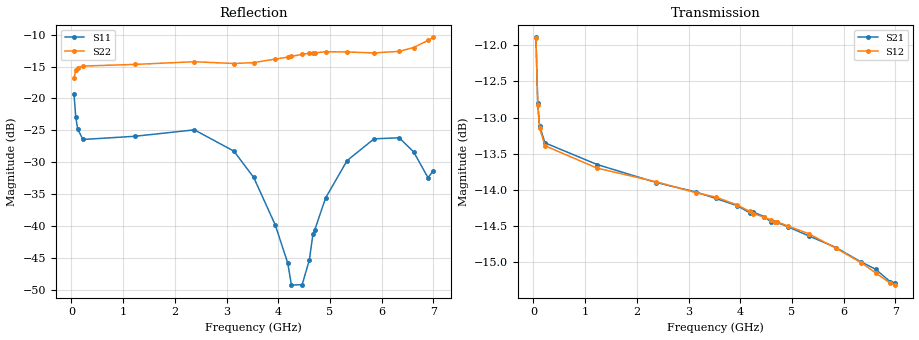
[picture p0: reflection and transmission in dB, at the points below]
! Integrated Device Technology
! Corporate Headquarters
! 6024 Silver Creek Valley Road
! San Jose, CA 95138  USA
! Phone:  1-408-284-8200
! Toll Free:  1-800-223-1366
! Webpage:  http://www.idt.com/
! Timing and RF Division
! 515 Groton Road, Suite 102
! Westford, MA 01886-6024
! Device:  F2258
! Description: Voltage Variable RF Attenuator
! Frequency:  50.0 -  6000.00 MHz
! Package:  3x3 mm Thin QFN Plastic Package: 16 pin
! Ports:  2 RF, 2 DC
!  Pin  1  = NC
!  Pin  2  = NC
!  Pin  3  = RF2  = Port 2
!  Pin  4  = GND
!  Pin  5  = Vdd
!  Pin  6  = NC
!  Pin  7  = VCTRL
!  Pin  8  = NC
!  Pin  9  = GND
!  Pin 10  = RF1  = Port 1
!  Pin 11  = NC
!  Pin 12  = NC
!  Pin 13  = NC
!  Pin 14  = NC
!  Pin 15  = NC
!  Pin 16  = NC
! Vcntrl:  1.130 Volts
! Vdd:  +3.300 Volts
! Current:  1.162 mA
! Data:  The device was measured on a the F2258 evaluation board which has
!  individual transmission lines to the RF pins.  Data was collected
!  using a calibrated network analyzer.  The evaluation board was
!  de-embedded using a TRL calibration technique.
!  The reference plane is the edge of the package pin.
! Misc:  SN 10
!  Action Tracker AT0285
! Date Measured:  2014-12-10
! Date:  2016-01-13  MJV
! Note:
!  Integrated Device Technology supplies this data as a sample of measured
!  data at the package pin for this product.  Your particular data for this
!  product may vary.
!  Data was taken at 25 degrees C.
!  Integrated Device Technology reserves the right to change this data at anytime.
!Freq_(GHz)  S11M_(dB)  S11P_(deg)  S21M_(dB)  S21P_(deg)  S12M_(dB)  S12P_(deg)  S22M_(dB)  S22P_(deg)
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# GHz S dB R 50
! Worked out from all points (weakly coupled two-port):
!   201 points, 50 MHz to 7 GHz, reference 50 ohm
!   highest |S21| = -11.89 dB at 50 MHz (marker M1); lowest = -15.3 dB at 7 GHz (marker M2)
!   lowest |S11| = -49.3 dB at 4.255 GHz (marker M3), VSWR 1.01, Z = 50.3 + j0.0738 ohm
!   |S11| at or under -10 dB: start of sweep to end of sweep
!   |S22| runs from -16.8 to -10.4 dB; largest |S21 - S12| = 0.0013
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0.05  -19.24 -87.7  -11.89 -20.8  -11.90 -20.8  -16.85 -24.7
0.08475  -22.93 -68.2  -12.80 -14.8  -12.83 -14.9  -15.59 -13.7
0.1195  -24.75 -53.7  -13.11 -12.0  -13.14 -12.0  -15.21 -11.1
0.22375  -26.45 -32.2  -13.35 -9.4  -13.39 -9.4  -14.93 -10.3
1.2315  -25.95 -16.8  -13.65 -21.0  -13.70 -21.0  -14.67 -36.4
2.37825  -24.94 -7.6  -13.90 -38.1  -13.89 -38.1  -14.25 -65.0
3.14275  -28.28 1.0  -14.03 -49.8  -14.04 -49.8  -14.53 -89.1
3.525  -32.40 7.5  -14.12 -55.8  -14.10 -55.8  -14.39 -104.2
3.942  -39.86 14.7  -14.22 -62.2  -14.21 -62.2  -13.84 -119.1
4.18525  -45.88 22.2  -14.32 -65.8  -14.30 -65.8  -13.53 -126.1
4.25475  -49.31 12.4  -14.31 -66.9  -14.33 -66.9  -13.39 -127.9
4.46325  -49.23 -40.1  -14.37 -70.1  -14.38 -70.1  -13.11 -133.5
4.60225  -45.33 -47.5  -14.45 -72.1  -14.42 -72.1  -12.90 -135.9
4.67175  -41.27 -45.9  -14.44 -73.2  -14.44 -73.1  -12.90 -136.8
4.7065  -40.64 -46.7  -14.45 -73.6  -14.44 -73.6  -12.87 -137.7
4.915  -35.64 -44.3  -14.51 -76.7  -14.50 -76.7  -12.68 -140.8
5.332  -29.76 -32.0  -14.64 -82.8  -14.61 -82.8  -12.72 -146.8
5.85325  -26.35 -18.2  -14.80 -90.2  -14.81 -90.2  -12.87 -156.1
6.33975  -26.19 -2.9  -15.00 -97.2  -15.01 -97.3  -12.62 -168.4
6.61775  -28.40 17.7  -15.10 -101.0  -15.15 -101.0  -12.02 -176.2
6.89575  -32.44 68.5  -15.27 -104.7  -15.29 -104.7  -10.90 176.5
7  -31.35 99.1  -15.29 -106.0  -15.32 -106.0  -10.43 174.0
